VERSION 5.7 ;
  NOWIREEXTENSIONATPIN ON ;
  DIVIDERCHAR "/" ;
  BUSBITCHARS "[]" ;
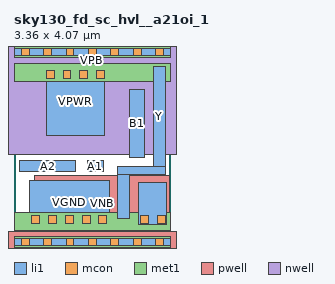
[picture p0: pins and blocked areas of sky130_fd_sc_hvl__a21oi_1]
MACRO sky130_fd_sc_hvl__a21oi_1
  CLASS BLOCK ;
  FOREIGN sky130_fd_sc_hvl__a21oi_1 ;
  ORIGIN 0.000 0.000 ;
  SIZE 3.360 BY 4.070 ;
  PIN A1
    ANTENNAGATEAREA 1.125000 ;
    PORT
      LAYER li1 ;
        RECT 1.565 1.505 1.915 1.750 ;
    END
  END A1
  PIN A2
    ANTENNAGATEAREA 1.125000 ;
    PORT
      LAYER li1 ;
        RECT 0.125 1.505 1.315 1.750 ;
    END
  END A2
  PIN B1
    ANTENNAGATEAREA 1.125000 ;
    PORT
      LAYER li1 ;
        RECT 2.470 1.805 2.800 3.260 ;
    END
  END B1
  PIN VGND
    USE GROUND ;
    PORT
      LAYER li1 ;
        RECT 0.330 0.365 2.040 1.325 ;
        RECT 2.675 0.365 3.265 1.275 ;
      LAYER mcon ;
        RECT 0.380 0.395 0.550 0.565 ;
        RECT 0.740 0.395 0.910 0.565 ;
        RECT 1.100 0.395 1.270 0.565 ;
        RECT 1.460 0.395 1.630 0.565 ;
        RECT 1.820 0.395 1.990 0.565 ;
        RECT 2.705 0.395 2.875 0.565 ;
        RECT 3.065 0.395 3.235 0.565 ;
      LAYER met1 ;
        RECT 0.000 0.255 3.360 0.625 ;
    END
  END VGND
  PIN VNB
    ANTENNADIFFAREA 0.571200 ;
    PORT
      LAYER pwell ;
        RECT 0.440 0.215 3.340 1.415 ;
        RECT -0.130 -0.215 3.490 0.215 ;
      LAYER li1 ;
        RECT 0.000 -0.085 3.360 0.085 ;
      LAYER mcon ;
        RECT 0.155 -0.085 0.325 0.085 ;
        RECT 0.635 -0.085 0.805 0.085 ;
        RECT 1.115 -0.085 1.285 0.085 ;
        RECT 1.595 -0.085 1.765 0.085 ;
        RECT 2.075 -0.085 2.245 0.085 ;
        RECT 2.555 -0.085 2.725 0.085 ;
        RECT 3.035 -0.085 3.205 0.085 ;
      LAYER met1 ;
        RECT 0.000 -0.115 3.360 0.115 ;
    END
  END VNB
  PIN VPB
    ANTENNADIFFAREA 0.571200 ;
    PORT
      LAYER nwell ;
        RECT -0.330 1.885 3.690 4.485 ;
      LAYER li1 ;
        RECT 0.000 3.985 3.360 4.155 ;
      LAYER mcon ;
        RECT 0.155 3.985 0.325 4.155 ;
        RECT 0.635 3.985 0.805 4.155 ;
        RECT 1.115 3.985 1.285 4.155 ;
        RECT 1.595 3.985 1.765 4.155 ;
        RECT 2.075 3.985 2.245 4.155 ;
        RECT 2.555 3.985 2.725 4.155 ;
        RECT 3.035 3.985 3.205 4.155 ;
      LAYER met1 ;
        RECT 0.000 3.955 3.360 4.185 ;
    END
  END VPB
  PIN VPWR
    USE POWER ;
    PORT
      LAYER li1 ;
        RECT 0.690 2.280 1.940 3.755 ;
      LAYER mcon ;
        RECT 0.690 3.505 0.860 3.675 ;
        RECT 1.050 3.505 1.220 3.675 ;
        RECT 1.410 3.505 1.580 3.675 ;
        RECT 1.770 3.505 1.940 3.675 ;
      LAYER met1 ;
        RECT 0.000 3.445 3.360 3.815 ;
    END
  END VPWR
  PIN Y
    ANTENNADIFFAREA 0.832500 ;
    PORT
      LAYER li1 ;
        RECT 2.980 1.625 3.235 3.755 ;
        RECT 2.220 1.455 3.235 1.625 ;
        RECT 2.220 0.495 2.470 1.455 ;
    END
  END Y
  OBS
      LAYER li1 ;
        RECT 0.260 2.100 0.510 3.755 ;
        RECT 2.120 2.100 2.290 3.755 ;
        RECT 0.260 1.930 2.290 2.100 ;
  END
END sky130_fd_sc_hvl__a21oi_1
END LIBRARY

